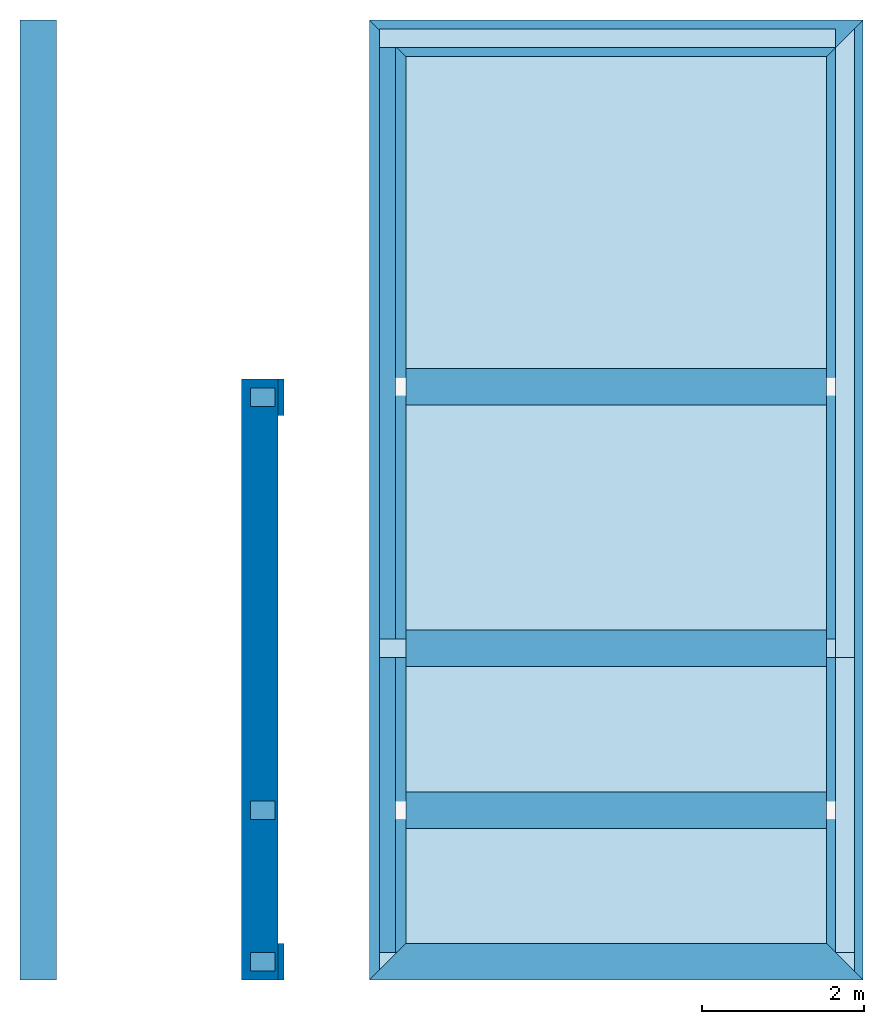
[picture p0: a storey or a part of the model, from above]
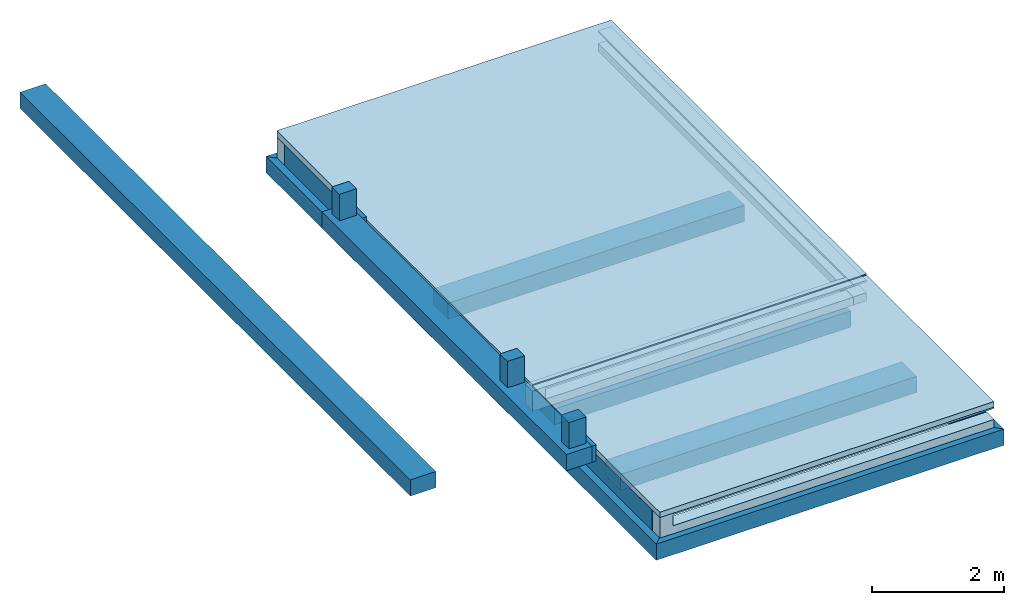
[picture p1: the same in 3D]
Properties of the parts of a building model (IFC2X3)

# File
Description: ViewDefinition [CoordinationView_V2.0], Option [Drawing Scale: 100.000000], Option [Elements to export: Visible elements (on all stories)], Option [Partial Structure Display: Entire Model], Option [IFC Domain: All], Option [Structural Function: All Elements], Option [Convert Grid elements: On], Option [Convert IFC Annotations and ARCHICAD 2D elements: Off], Option [Convert 2D symbols of Doors and Windows: Off], Option [Export geometries that Participates in Collision Detection only: Off], Option [Split complex elements: Off], Option [Material Preservation: Explode where necessary], Option [Elements in Solid Element Operations: Extruded/revolved], Option [Elements with junctions: Extruded/revolved without junctions], Option [Slabs with slanted edge(s): Extruded], Option [IFC Site Location: At Project Origin], Option [Curtain Wall export mode: Container Element], Option [Railing export mode: Single Element], Option [Stair export mode: Container Element], Option [Properties To Export: All properties], Option [Space containment: Off], Option [Bounding Box: Off], Option [Geometry to type objects: Off], Option [Element Properties: Off], Option [Building Material Properties: Off], Option [Element Parameters: Off], Option [Component Parameters: Off], Option [IFC Base Quantities: Off], Option [Door Window Parameters: Off], Option [IFC Space boundaries: Off], Option [ARCHICAD Zone Categories as IFC Space classification data: Off], Option [Element Classifications: On]
File name: C:\Users\tonyp\Desktop\MAQUETTE VILLA BASILE.ifc
Time: 2022-10-12T11:11:28
Author: Nom de famille Prénom
Organization: (Atelier d'architecture.... )
Written by: The EXPRESS Data Manager Version 5.02.0100.09 : 26 Sep 2013
Made in: IFC file generated by GRAPHISOFT ARCHICAD 24.0.0 FRA FULL Windows version (IFC add-on version: 3008 FRA FULL).
Authorization: Nom de famille Prénom

# IfcProject, (Construction de... )
Phase: (provisoire, définitif...)

# IfcSite, Site
RefLatitude: 46, 10, 0, 0; RefLongitude: 6, 9, 0, 0; RefElevation: 425 m

# IfcBuildingStorey (5)
In: Bâtiment
Name | Elevation (m)
FONDATIONS | -2.8
SOUS-SOL | 0
RDJ | 3
COMBLES | 6
TOITURE | 9

# IfcBuildingElementProxy (9)
AC_Pset_RenovationAndPhasing - Renovation Status: Existing
Name | In
2 x MOB-1224 | SOUS-SOL
6 x MOB-1224 | RDJ
MOB-1224 | COMBLES

# IfcBuildingElementProxy: ARBRE DU VOYAGEUR, Symb-0004
In: TOITURE
Classification: Elément de construction non défini (Classification ARCHICAD)
AC_Pset_RenovationAndPhasing - Renovation Status: Existing

# IfcBuildingElementProxy: Baignoire 24, MOB-1155
In: RDJ
AC_Pset_RenovationAndPhasing - Renovation Status: Existing

# IfcBuildingElementProxy: Berline 02 24, Symb-0002
In: TOITURE
Classification: Elément de construction non défini (Classification ARCHICAD)
AC_Pset_RenovationAndPhasing - Renovation Status: Existing

# IfcBuildingElementProxy: Cabine de douche 24, MOB-1157
In: RDJ
AC_Pset_RenovationAndPhasing - Renovation Status: Existing

# IfcBuildingElementProxy: Chevron RM 20 (88)
In: TOITURE
AC_Pset_RenovationAndPhasing - Renovation Status: Existing
Name
2 x MOB-1202
2 x MOB-1189
2 x MOB-1206
2 x MOB-1221
2 x MOB-1204
2 x MOB-1223
2 x MOB-1196
2 x MOB-1208
2 x MOB-1197
2 x MOB-1205
2 x MOB-1185
2 x MOB-1187
2 x MOB-1192
2 x MOB-1190
2 x MOB-1199
2 x MOB-1176
2 x MOB-1167
2 x MOB-1219
2 x MOB-1195
2 x MOB-1198
2 x MOB-1207
2 x MOB-1165
2 x MOB-1173
2 x MOB-1200
2 x MOB-1164
2 x MOB-1220
2 x MOB-1224
2 x MOB-1188
2 x MOB-1174
2 x MOB-1163
2 x MOB-1203
2 x MOB-1178
2 x MOB-1201
2 x MOB-1209
2 x MOB-1184
2 x MOB-1191
2 x MOB-1194
2 x MOB-1168
2 x MOB-1186
2 x MOB-1175
2 x MOB-1177
2 x MOB-1166
2 x MOB-1193
2 x MOB-1222

# IfcBuildingElementProxy: Chevron d'arêtier RM 20 (4)
In: TOITURE
AC_Pset_RenovationAndPhasing - Renovation Status: Existing
Name
2 x MOB-1179
2 x MOB-1180

# IfcBuildingElementProxy: Elément bas d'angle L 24 (2)
In: RDJ
AC_Pset_RenovationAndPhasing - Renovation Status: Existing

# IfcBuildingElementProxy: Elément bas d'angle S 24, MOB-1381
In: SOUS-SOL
AC_Pset_RenovationAndPhasing - Renovation Status: Existing

# IfcBuildingElementProxy: Elément haut double avec four 24, MOB-1204
In: RDJ
AC_Pset_RenovationAndPhasing - Renovation Status: Existing

# IfcBuildingElementProxy: Elément simple avec trois portes 21 (2)
AC_Pset_RenovationAndPhasing - Renovation Status: Existing
Name | In
MOB-1260 | SOUS-SOL
MOB-1203 | RDJ

# IfcBuildingElementProxy: Empannon RM 20 (22)
In: TOITURE
AC_Pset_RenovationAndPhasing - Renovation Status: Existing
Name
2 x MOB-1214
2 x MOB-1171
2 x MOB-1169
2 x MOB-1170
2 x MOB-1172
2 x MOB-1211
2 x MOB-1215
2 x MOB-1212
2 x MOB-1213
2 x MOB-1217
2 x MOB-1216

# IfcBuildingElementProxy: Gouttière 24 (2)
In: TOITURE
AC_Pset_RenovationAndPhasing - Renovation Status: Existing

# IfcBuildingElementProxy: IfcBuildingElementProxy (16)
In: RDJ
AC_Pset_RenovationAndPhasing - Renovation Status: Existing
Name | Material
VOLEE-001 | Bois - Massif 01
MARCHE-001 | Finition sol - Parquet
MARCHE-002 | Finition sol - Parquet
MARCHE-003 | Finition sol - Parquet
MARCHE-004 | Finition sol - Parquet
MARCHE-005 | Finition sol - Parquet
MARCHE-006 | Finition sol - Parquet
MARCHE-007 | Finition sol - Parquet
MARCHE-008 | Finition sol - Parquet
MARCHE-009 | Finition sol - Parquet
MARCHE-010 | Finition sol - Parquet
MARCHE-011 | Finition sol - Parquet
MARCHE-012 | Finition sol - Parquet
MARCHE-013 | Finition sol - Parquet
MARCHE-014 | Finition sol - Parquet
MARCHE-033 | Finition sol - Parquet

# IfcBuildingElementProxy: Kit de douche 24, MOBILIER-0020
In: SOUS-SOL
Classification: Toilettes (Classification ARCHICAD)
AC_Pset_RenovationAndPhasing - Renovation Status: Existing

# IfcBuildingElementProxy: Lavabo sur meuble 21 (3)
AC_Pset_RenovationAndPhasing - Renovation Status: Existing
Name | In
MOB-0599 | SOUS-SOL
2 x MOB-1156 | RDJ

# IfcBuildingElementProxy: Minispace 24, Symb-0003
In: TOITURE
Classification: Elément de construction non défini (Classification ARCHICAD)
AC_Pset_RenovationAndPhasing - Renovation Status: Existing

# IfcBuildingElementProxy: Modèle herbe 24 (3)
In: TOITURE
Classification: Elément de construction non défini (Classification ARCHICAD)
AC_Pset_RenovationAndPhasing - Renovation Status: Existing

# IfcBuildingElementProxy: Panne 20 (10)
In: TOITURE
AC_Pset_RenovationAndPhasing - Renovation Status: Existing

# IfcBuildingElementProxy: Portail 1, Symb-0002
In: TOITURE
AC_Pset_RenovationAndPhasing - Renovation Status: Existing

# IfcBuildingElementProxy: Poteau 1 24 (2)
In: SOUS-SOL
Classification: Membre (Classification ARCHICAD); Material: Bois massif
AC_Pset_RenovationAndPhasing - Renovation Status: Existing

# IfcBuildingElementProxy: Tirant 24 (2)
In: SOUS-SOL
Classification: Membre (Classification ARCHICAD); Material: Bois massif
AC_Pset_RenovationAndPhasing - Renovation Status: Existing

# IfcBuildingElementProxy: Tuyau descente complexe 24 (2)
In: TOITURE
AC_Pset_RenovationAndPhasing - Renovation Status: Existing

# IfcBuildingElementProxy: WC 24 (4)
AC_Pset_RenovationAndPhasing - Renovation Status: Existing
Name | In
Symb-0002 | SOUS-SOL
2 x Symb-0002 | RDJ
Symb-0002 | COMBLES

# IfcDiscreteAccessory: Type d'escalier, ESCALIER-001
In: RDJ
Classification: Accessoire distinct (Classification ARCHICAD)
AC_Pset_RenovationAndPhasing - Renovation Status: Existing

# IfcDistributionElement: Lavabo 24, MOB-1156
In: COMBLES
Classification: Elément de distribution (Classification ARCHICAD)
AC_Pset_RenovationAndPhasing - Renovation Status: Existing

# IfcDoor: Porte 24 (3)
Type - OperationType: SINGLE_SWING_LEFT; ParameterTakesPrecedence: no; Sizeable: no
OverallHeight: 2.1 m; OverallWidth: 0.93 m; Classification: Porte (Classification ARCHICAD)
Pset_DoorCommon - ThermalTransmittance: 0
AC_Pset_RenovationAndPhasing - Renovation Status: Existing
Name | In
Por-053 | RDJ
Por-049 | RDJ
Por-052 | COMBLES

# IfcDoor: Porte 24 (6)
Type - OperationType: SINGLE_SWING_RIGHT; ParameterTakesPrecedence: no; Sizeable: no
OverallHeight: 2.1 m; Classification: Porte (Classification ARCHICAD)
Pset_DoorCommon - ThermalTransmittance: 0
AC_Pset_RenovationAndPhasing - Renovation Status: Existing
Name | In | OverallWidth (m)
2 x Por-049 | SOUS-SOL | 0.93
Por-050 | RDJ | 1.03
Por-050 | RDJ | 0.93
Por-052 | RDJ | 0.93
Por-052 | COMBLES | 0.93

# IfcDoor: Porte coulissante 24 (4)
Type - OperationType: USERDEFINED; ParameterTakesPrecedence: no; Sizeable: no
OverallHeight: 2.2 m; Classification: Porte (Classification ARCHICAD)
Pset_DoorCommon - ThermalTransmittance: 0
AC_Pset_RenovationAndPhasing - Renovation Status: Existing
Name | In | OverallWidth (m) | GlazingAreaFraction
Por-023 | SOUS-SOL | 2 | 2.8272
2 x Por-023 | RDJ | 2 | 2.8272
Por-023 | COMBLES | 1.6 | 2.0832

# IfcDoor: Porte pliante coulissante panneaux multiples 24, Por-056
In: SOUS-SOL
Type - OperationType: USERDEFINED; ParameterTakesPrecedence: no; Sizeable: no
OverallHeight: 2.1 m; OverallWidth: 1.68527 m; Classification: Porte (Classification ARCHICAD)
Pset_DoorCommon - ThermalTransmittance: 0
AC_Pset_RenovationAndPhasing - Renovation Status: Existing

# IfcFooting (9)
In: FONDATIONS
Classification: Fondation (Classification ARCHICAD); Material: Hachure solide 2628782308
AC_Pset_RenovationAndPhasing - Renovation Status: Existing
Name
5 x MurExt-002
2 x Mur-037
MurExt-014
MurExt-013

# IfcSlab: Finition ext - Crépis 10 (2)
In: TOITURE
Type - PredefinedType: ROOF
Classification: Toit (Classification ARCHICAD); Material: Finition ext - Crépis 0.01 m
AC_Pset_RenovationAndPhasing - Renovation Status: Existing

# IfcSlab: Hachure solide 2628782308 100 (2)
Type - PredefinedType: FLOOR
Classification: Dalle (Classification ARCHICAD); Material: Hachure solide 2628782308 0.1 m
AC_Pset_RenovationAndPhasing - Renovation Status: Existing
Name | In
Dalle-011 | FONDATIONS
Dalle-009 | COMBLES

# IfcSlab: Hachure solide 2628782308 120 (3)
Type - PredefinedType: FLOOR
Classification: Dalle (Classification ARCHICAD); Material: Hachure solide 2628782308 0.12 m
AC_Pset_RenovationAndPhasing - Renovation Status: Existing
Name | In
Dalle-009 | FONDATIONS
Dalle-011 | SOUS-SOL
Dalle-009 | COMBLES

# IfcSlab: Hachure solide 2628782308 140, Dalle-010
In: SOUS-SOL
Type - PredefinedType: FLOOR
Classification: Dalle (Classification ARCHICAD); Material: Hachure solide 2628782308 0.14 m
AC_Pset_RenovationAndPhasing - Renovation Status: Existing

# IfcSlab: Hachure solide 2628782308 20, Dalle-011
In: RDJ
Type - PredefinedType: FLOOR
Classification: Dalle (Classification ARCHICAD); Material: Hachure solide 2628782308 0.02 m
AC_Pset_RenovationAndPhasing - Renovation Status: Existing

# IfcSlab: Sans Trame* 2635859640 20 (19)
In: SOUS-SOL
Type - PredefinedType: FLOOR
Classification: Dalle (Classification ARCHICAD); Material: Sans Trame* 2635859640 0.02 m
AC_Pset_RenovationAndPhasing - Renovation Status: Existing

# IfcSlab: Sans Trame* 3165822909 10 (2)
In: TOITURE
Type - PredefinedType: ROOF
Classification: Toit (Classification ARCHICAD); Material: Sans Trame* 3165822909 0.01 m
AC_Pset_RenovationAndPhasing - Renovation Status: Existing

# IfcSlab: Sans Trame* 3165822909 20 (8)
In: TOITURE
Type - PredefinedType: ROOF
Classification: Toit (Classification ARCHICAD); Material: Sans Trame* 3165822909 0.02 m
AC_Pset_RenovationAndPhasing - Renovation Status: Existing
Name
4 x Toit-01
4 x Toit-06

# IfcSlab: Sans Trame* 3165822909 5 (4)
In: TOITURE
Type - PredefinedType: ROOF
Classification: Toit (Classification ARCHICAD); Material: Sans Trame* 3165822909 0.005 m
AC_Pset_RenovationAndPhasing - Renovation Status: Existing

# IfcSlab: Struct. - Chape 100, Dalle-012
In: TOITURE
Type - PredefinedType: FLOOR
Classification: Dalle (Classification ARCHICAD); Material: Struct. - Chape 0.1 m
AC_Pset_RenovationAndPhasing - Renovation Status: Existing

# IfcSlab: Struct. - Chape 150, Dalle-011
In: TOITURE
Type - PredefinedType: FLOOR
Classification: Dalle (Classification ARCHICAD); Material: Struct. - Chape 0.15 m
AC_Pset_RenovationAndPhasing - Renovation Status: Existing

# IfcSlab: Struct. - Chape 200 (4)
In: TOITURE
Type - PredefinedType: FLOOR
Classification: Dalle (Classification ARCHICAD); Material: Struct. - Chape 0.2 m
AC_Pset_RenovationAndPhasing - Renovation Status: Existing
Name
2 x Dalle-013
2 x Dalle-012

# IfcSlab: Struct. - Chape 50 (6)
Type - PredefinedType: FLOOR
Classification: Dalle (Classification ARCHICAD); Material: Struct. - Chape 0.05 m
AC_Pset_RenovationAndPhasing - Renovation Status: Existing
Name | In
Dalle-010 | SOUS-SOL
Dalle-011 | SOUS-SOL
Dalle-011 | RDJ
Dalle-010 | RDJ
Dalle-012 | COMBLES
Dalle-013 | COMBLES

# IfcWall: Hachure solide 2628782308, MurExt-010
In: RDJ
Classification: Mur (Classification ARCHICAD); Material: Hachure solide 2628782308
AC_Pset_RenovationAndPhasing - Renovation Status: Existing

# IfcWall: Hachure solide 2628782308 200 (2)
In: SOUS-SOL
Classification: Mur (Classification ARCHICAD); Material: Hachure solide 2628782308
AC_Pset_RenovationAndPhasing - Renovation Status: Existing
Name
MurExt-011
MurExt-003

# IfcWall: Hachure solide 2628782308 230 (37)
Classification: Mur (Classification ARCHICAD); Material: Hachure solide 2628782308
AC_Pset_RenovationAndPhasing - Renovation Status: Existing
Name | In
MurExt-012 | SOUS-SOL
3 x MurExt-05 | SOUS-SOL
MurExt-007 | SOUS-SOL
2 x MurExt-018 | SOUS-SOL
2 x MurExt-006 | SOUS-SOL
MurExt-013 | SOUS-SOL
MurExt-017 | SOUS-SOL
MurExt-004 | SOUS-SOL
MurExt-019 | SOUS-SOL
2 x MurExt-020 | SOUS-SOL
MurExt-005 | SOUS-SOL
MurExt-006 | SOUS-SOL | Pset_WallCommon - LoadBearing: yes; IsExternal: yes
MurExt-005 | RDJ
2 x MurExt-011 | RDJ
MurExt-012 | RDJ
MurExt-010 | RDJ
3 x MurExt-008 | RDJ
MurExt-009 | RDJ
MurExt-004 | RDJ
3 x MurExt-017 | COMBLES
MurExt-014 | COMBLES
MurExt-018 | COMBLES
MurExt-011 | COMBLES
MurExt-013 | COMBLES
2 x MurExt-016 | COMBLES
MurExt-012 | COMBLES

# IfcWall: Hachure solide 2628782308 230 - 230, MurExt-018
In: COMBLES
Classification: Mur (Classification ARCHICAD); Material: Hachure solide 2628782308
AC_Pset_RenovationAndPhasing - Renovation Status: Existing

# IfcWall: Hachure solide 2628782308 70 (10)
Classification: Mur (Classification ARCHICAD); Material: Hachure solide 2628782308
AC_Pset_RenovationAndPhasing - Renovation Status: Existing
Name | In
MurExt-004 | SOUS-SOL
MurExt-020 | SOUS-SOL
2 x MurExt-011 | RDJ
MurExt-010 | RDJ
MurExt-008 | RDJ
MurExt-013 | COMBLES
MurExt-012 | COMBLES
MurExt-004 | COMBLES
MurExt-005 | COMBLES

# IfcWallStandardCase: Hachure solide 2628782308 230 (33)
Classification: Mur (Classification ARCHICAD); Material: Hachure solide 2628782308 0.23 m
AC_Pset_RenovationAndPhasing - Renovation Status: Existing
Name | In
3 x MurExt-017 | FONDATIONS
MurExt-05 | SOUS-SOL
MurExt-018 | SOUS-SOL
2 x MurExt-008 | RDJ
MurExt-010 | RDJ
2 x MurExt-015 | COMBLES
2 x MurExt-018 | COMBLES
4 x MurExt-004 | COMBLES
MurExt-016 | COMBLES
6 x MurExt-011 | TOITURE
3 x MurExt-012 | TOITURE
2 x MurExt-013 | TOITURE
MurExt-014 | TOITURE
MurExt-015 | TOITURE
MurExt-016 | TOITURE
MurExt-017 | TOITURE
MurExt-019 | TOITURE

# IfcWallStandardCase: Hachure solide 2628782308 450 (11)
In: FONDATIONS
Classification: Mur (Classification ARCHICAD); Material: Hachure solide 2628782308 0.45 m
AC_Pset_RenovationAndPhasing - Renovation Status: Existing
Name
8 x MurExt-017
MurExt-015
2 x MurExt-018

# IfcWallStandardCase: Hachure solide 2628782308 70, MurExt-020
In: SOUS-SOL
Classification: Mur (Classification ARCHICAD); Material: Hachure solide 2628782308 0.07 m
AC_Pset_RenovationAndPhasing - Renovation Status: Existing

# IfcWallStandardCase: MUR VILLA 10 (72)
In: SOUS-SOL
Classification: Mur (Classification ARCHICAD); Material: MUR VILLA 0.01 m
AC_Pset_RenovationAndPhasing - Renovation Status: Existing
Pset_WallCommon - LoadBearing: yes; IsExternal: yes

# IfcWindow: Baie_fixe (5)
Type - ParameterTakesPrecedence: no; Sizeable: no
Classification: Fenêtre (Classification ARCHICAD)
AC_Pset_RenovationAndPhasing - Renovation Status: Existing
Name | In | OverallHeight (m) | OverallWidth (m)
Fen-032 | SOUS-SOL | 0.6 | 0.6
Fen-033 | RDJ | 1 | 0.5
Fen-032 | RDJ | 1 | 0.5
Fen-032 | COMBLES | 0.5 | 0.5
Fen-033 | COMBLES | 0.5 | 0.5

# IfcWindow: Fenêtre 2v (8)
Type - ParameterTakesPrecedence: no; Sizeable: no
OverallHeight: 1.2 m; OverallWidth: 1.2 m; Classification: Fenêtre (Classification ARCHICAD)
AC_Pset_RenovationAndPhasing - Renovation Status: Existing
Name | In
2 x Fen-009 | SOUS-SOL
Fen-009 | RDJ
2 x Fen-012 | RDJ
Fen-010 | RDJ
Fen-013 | RDJ
Fen-010 | COMBLES
